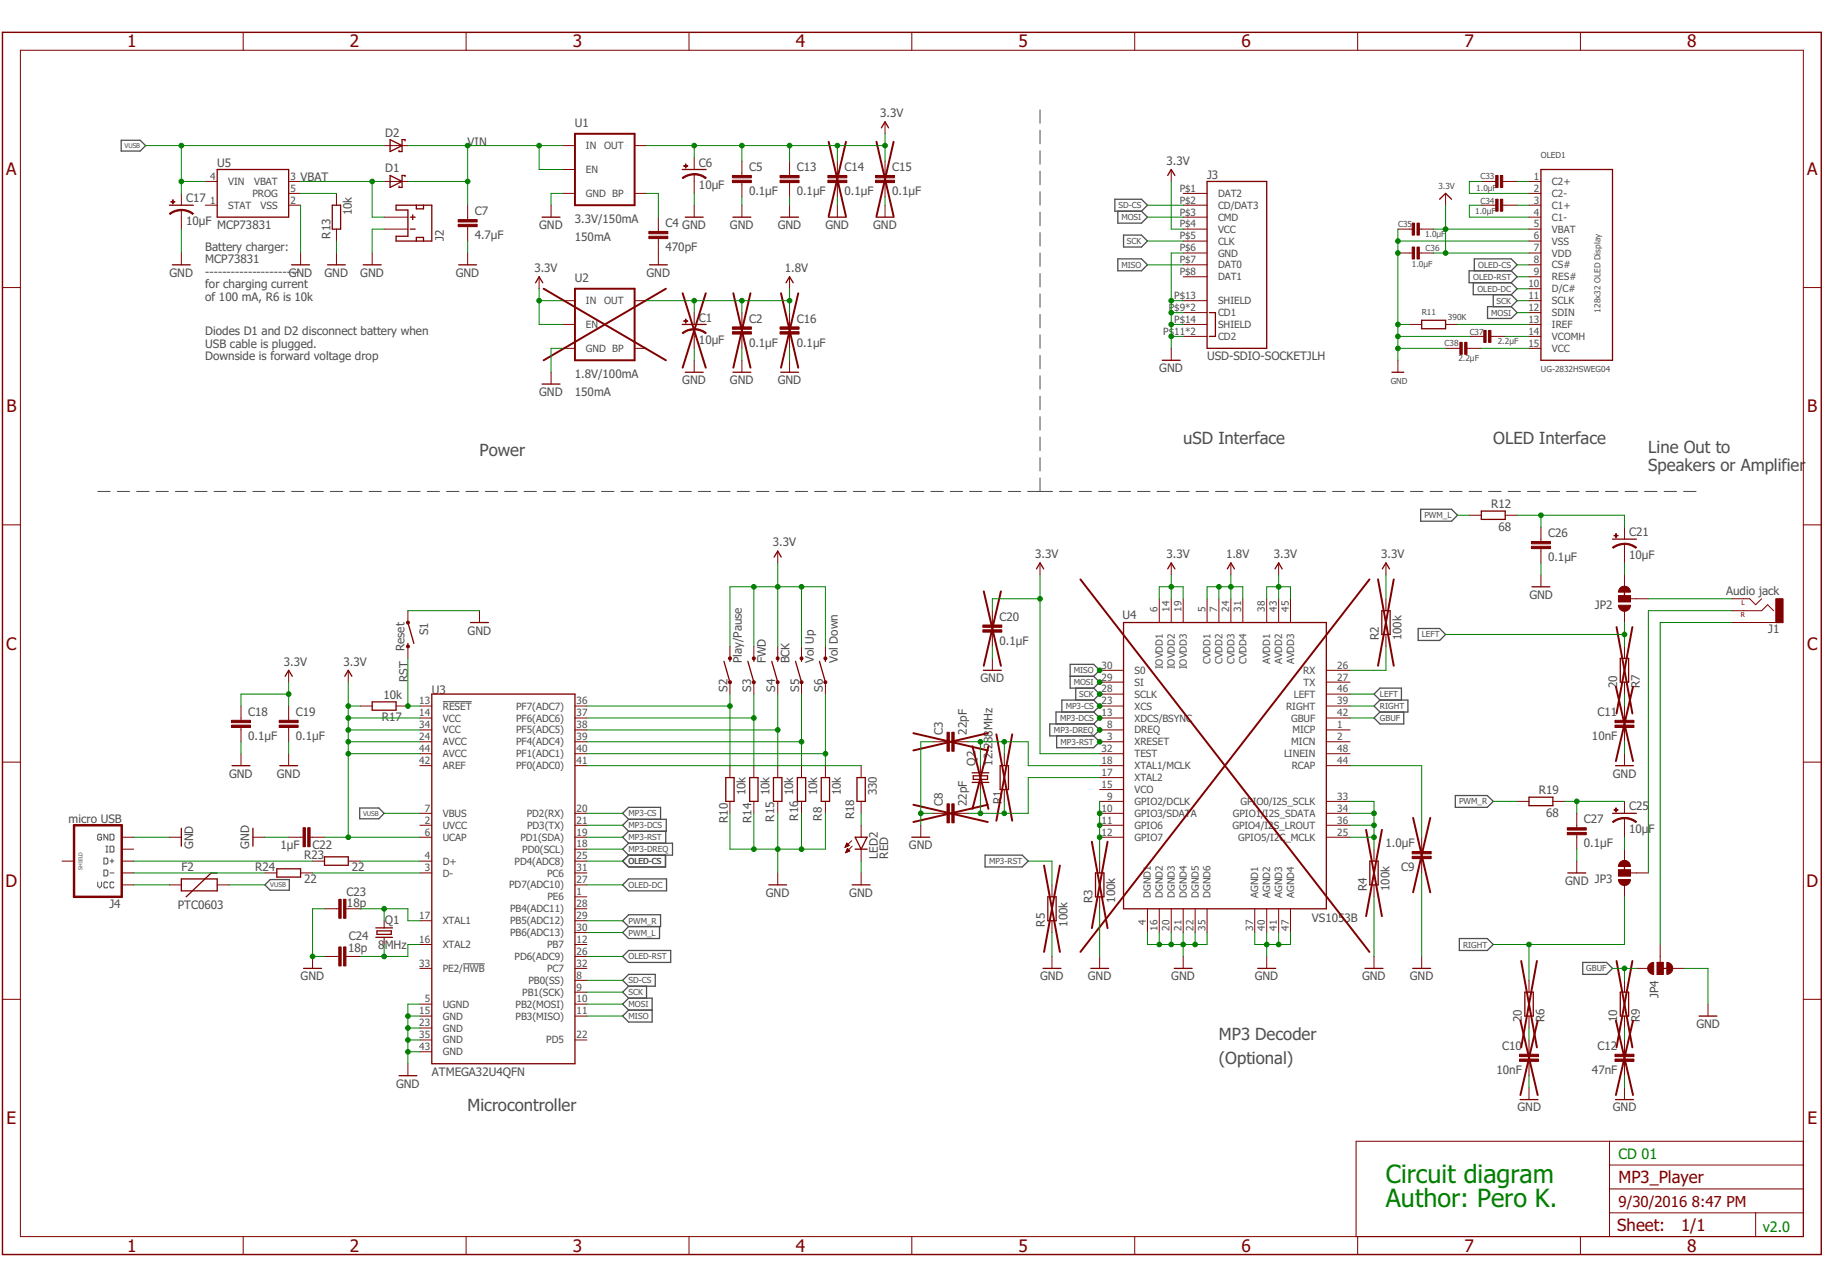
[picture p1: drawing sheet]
<svg xmlns="http://www.w3.org/2000/svg" width="297mm" height="210mm" viewBox="0 0 297 210" stroke-linecap="round" stroke-linejoin="round" font-family="sans-serif">
<defs><g id="words">
<g font-size="4.1" fill="#008000">
<text x="225.8" y="192.8">Circuit diagram</text>
<text x="225.8" y="196.7">Author: Pero K.</text>
</g>
<g font-size="2.8" fill="#800000">
<text x="20.7" y="7.7">1</text>
<text x="57" y="7.7">2</text>
<text x="93.3" y="7.7">3</text>
<text x="129.7" y="7.7">4</text>
<text x="166" y="7.7">5</text>
<text x="202.3" y="7.7">6</text>
<text x="238.6" y="7.7">7</text>
<text x="274.9" y="7.7">8</text>
<text x="1" y="28.5">A</text>
<text x="294.4" y="28.5">A</text>
<text x="1" y="67.2">B</text>
<text x="294.5" y="67.2">B</text>
<text x="1" y="105.9">C</text>
<text x="294.4" y="105.9">C</text>
<text x=".9" y="144.5">D</text>
<text x="294.3" y="144.5">D</text>
<text x="1.1" y="183.2">E</text>
<text x="294.5" y="183.2">E</text>
<text x="20.7" y="204">1</text>
<text x="57" y="204">2</text>
<text x="93.3" y="204">3</text>
<text x="129.7" y="204">4</text>
<text x="166" y="204">5</text>
<text x="202.3" y="204">6</text>
<text x="238.6" y="204">7</text>
<text x="274.9" y="204">8</text>
</g>
<g font-size="2.7" fill="#505050">
<text x="78.1" y="74.3">Power</text>
<text x="192.8" y="72.3">uSD Interface</text>
<text x="243.3" y="72.3">OLED Interface</text>
<text x="268.6" y="73.8">Line Out to</text>
<text x="268.6" y="76.7">Speakers or Amplifier</text>
<text x="198.6" y="169.5">MP3 Decoder</text>
<text x="198.6" y="173.4">(Optional)</text>
<text x="76.2" y="181.1">Microcontroller</text>
</g>
<g font-size="2.7" fill="#800000">
<text x="263.7" y="192.8">MP3_Player</text>
<text x="263.5" y="200.7">Sheet:</text>
<text x="273.9" y="200.6">1/1</text>
</g>
<g font-size="2.5" fill="#800000">
<text x="263.7" y="196.7">9/30/2016</text>
<text x="275.7" y="196.7">8:47 PM</text>
</g>
<g font-size="2.3" fill="#008000">
<text x="263.7" y="188.9">CD 01</text>
<text x="287.2" y="200.8">v2.0</text>
</g>
<g font-size="1.9" fill="#505050">
<text x="62.8" y="22.3">D2</text>
<text x="76.2" y="23.7">VIN</text>
<text x="93.7" y="20.6">U1</text>
<text x="143.4" y="19.1">3.3V</text>
<text x="35.4" y="27.2">U5</text>
<text x="49" y="29.6">VBAT</text>
<text x="62.8" y="28.1">D1</text>
<text x="113.9" y="27.1">C6</text>
<text x="122.1" y="27.9">C5</text>
<text x="129.8" y="27.9">C13</text>
<text x="137.6" y="27.9">C14</text>
<text x="145.4" y="27.9">C15</text>
<text x="190.1" y="26.8">3.3V</text>
<text x="196.7" y="29.2">J3</text>
<text x="30.3" y="33">C17</text>
<text x="57.3" y="35.1" transform="rotate(-90 57.3 35.1)">10k</text>
<text x="77.4" y="35.1">C7</text>
<text x="113.9" y="30.8">10µF</text>
<text x="122.1" y="31.8">0.1µF</text>
<text x="129.8" y="31.8">0.1µF</text>
<text x="137.6" y="31.8">0.1µF</text>
<text x="145.4" y="31.8">0.1µF</text>
<text x="30.3" y="36.7">10µF</text>
<text x="33.4" y="40.9">Battery charger:</text>
<text x="35.4" y="37.3">MCP73831</text>
<text x="53.9" y="38.9" transform="rotate(-90 53.9 38.9)">R13</text>
<text x="72.3" y="39.3" transform="rotate(-90 72.3 39.3)">J2</text>
<text x="77.4" y="39">4.7μF</text>
<text x="87.8" y="37.3">GND</text>
<text x="93.7" y="39.3">150mA</text>
<text x="93.7" y="36.4">3.3V/150mA</text>
<text x="108.4" y="40.9">470pF</text>
<text x="108.4" y="37">C4 GND</text>
<text x="118.9" y="37.3">GND</text>
<text x="126.7" y="37.3">GND</text>
<text x="134.5" y="37.3">GND</text>
<text x="142.3" y="37.3">GND</text>
<text x="27.6" y="45.1">GND</text>
<text x="33.4" y="42.9">MCP73831</text>
<text x="33.4" y="44.9">--------------------GND</text>
<text x="33.4" y="47">for charging current</text>
<text x="47.4" y="44.9">--</text>
<text x="52.9" y="45.1">GND</text>
<text x="58.7" y="45.1">GND</text>
<text x="74.2" y="45.1">GND</text>
<text x="87.1" y="44.3">3.3V</text>
<text x="93.7" y="45.9">U2</text>
<text x="105.3" y="45.1">GND</text>
<text x="127.9" y="44.3">1.8V</text>
<text x="33.4" y="49">of 100 mA, R6 is 10k</text>
<text x="113.9" y="52.4">C1</text>
<text x="122.1" y="52.6">C2</text>
<text x="129.8" y="52.6">C16</text>
<text x="33.4" y="54.6">Diodes D1 and D2 disconnect battery when</text>
<text x="33.4" y="56.7">USB cable is plugged.</text>
<text x="33.4" y="58.7">Downside is forward voltage drop</text>
<text x="113.9" y="56.1">10µF</text>
<text x="122.1" y="56.5">0.1µF</text>
<text x="129.8" y="56.5">0.1µF</text>
<text x="196.7" y="58.7">USD-SDIO-SOCKETJLH</text>
<text x="87.8" y="64.5">GND</text>
<text x="93.7" y="64.5">150mA</text>
<text x="93.7" y="61.6">1.8V/100mA</text>
<text x="111.2" y="62.6">GND</text>
<text x="118.9" y="62.6">GND</text>
<text x="126.7" y="62.6">GND</text>
<text x="188.9" y="60.7">GND</text>
<text x="243" y="82.8">R12</text>
<text x="125.9" y="89">3.3V</text>
<text x="244.2" y="86.5">68</text>
<text x="252.3" y="87.6">C26</text>
<text x="265.5" y="87.4">C21</text>
<text x="168.7" y="91">3.3V</text>
<text x="190.1" y="91">3.3V</text>
<text x="199.8" y="91">1.8V</text>
<text x="207.6" y="91">3.3V</text>
<text x="225" y="91">3.3V</text>
<text x="252.3" y="91.5">0.1µF</text>
<text x="265.5" y="91.1">10µF</text>
<text x="162.9" y="101.2">C20</text>
<text x="182.9" y="100.9">U4</text>
<text x="249.2" y="97.6">GND</text>
<text x="259.9" y="99.2">JP2</text>
<text x="281.3" y="97">Audio jack</text>
<text x="65.9" y="106.1" transform="rotate(-90 65.9 106.1)">Reset</text>
<text x="69.8" y="103.6" transform="rotate(-90 69.8 103.6)">S1</text>
<text x="76.2" y="103.4">GND</text>
<text x="162.9" y="105.1">0.1µF</text>
<text x="224.7" y="104.4" transform="rotate(-90 224.7 104.4)">R2</text>
<text x="228.3" y="104.4" transform="rotate(-90 228.3 104.4)">100k</text>
<text x="288.1" y="103.2">J1</text>
<text x="46.3" y="108.5">3.3V</text>
<text x="56" y="108.5">3.3V</text>
<text x="62.5" y="113.9">10k</text>
<text x="66.5" y="111.2" transform="rotate(-90 66.5 111.2)">RST</text>
<text x="70.4" y="113.1">U3</text>
<text x="118.5" y="112.7" transform="rotate(-90 118.5 112.7)">S2</text>
<text x="120.9" y="108.1" transform="rotate(-90 120.9 108.1)">Play/Pause</text>
<text x="122.4" y="112.7" transform="rotate(-90 122.4 112.7)">S3</text>
<text x="124.8" y="108.1" transform="rotate(-90 124.8 108.1)">FWD</text>
<text x="126.3" y="112.7" transform="rotate(-90 126.3 112.7)">S4</text>
<text x="128.7" y="108.1" transform="rotate(-90 128.7 108.1)">BCK</text>
<text x="130.2" y="112.7" transform="rotate(-90 130.2 112.7)">S5</text>
<text x="132.6" y="108.1" transform="rotate(-90 132.6 108.1)">Vol Up</text>
<text x="134.1" y="112.7" transform="rotate(-90 134.1 112.7)">S6</text>
<text x="136.5" y="108.1" transform="rotate(-90 136.5 108.1)">Vol Down</text>
<text x="159.8" y="111.2">GND</text>
<text x="263.5" y="112.1" transform="rotate(-90 263.5 112.1)">20</text>
<text x="267.2" y="112.1" transform="rotate(-90 267.2 112.1)">R7</text>
<text x="40.4" y="116.7">C18</text>
<text x="48.2" y="116.7">C19</text>
<text x="62.2" y="117.6">R17</text>
<text x="153.6" y="119.7" transform="rotate(-90 153.6 119.7)">C3</text>
<text x="157.5" y="119.7" transform="rotate(-90 157.5 119.7)">22pF</text>
<text x="260.3" y="116.7">C11</text>
<text x="40.4" y="120.6">0.1µF</text>
<text x="48.2" y="120.6">0.1µF</text>
<text x="159" y="124.8" transform="rotate(-90 159 124.8)">Q2</text>
<text x="161.7" y="124.8" transform="rotate(-90 161.7 124.8)">12.288MHz</text>
<text x="259.4" y="120.6">10nF</text>
<text x="37.3" y="126.7">GND</text>
<text x="45.1" y="126.7">GND</text>
<text x="121.5" y="129.6" transform="rotate(-90 121.5 129.6)">10k</text>
<text x="125.4" y="129.6" transform="rotate(-90 125.4 129.6)">10k</text>
<text x="129.2" y="129.6" transform="rotate(-90 129.2 129.6)">10k</text>
<text x="133.1" y="129.6" transform="rotate(-90 133.1 129.6)">10k</text>
<text x="137" y="129.6" transform="rotate(-90 137 129.6)">10k</text>
<text x="142.8" y="129.6" transform="rotate(-90 142.8 129.6)">330</text>
<text x="153.6" y="131.4" transform="rotate(-90 153.6 131.4)">C8</text>
<text x="157.5" y="131.4" transform="rotate(-90 157.5 131.4)">22pF</text>
<text x="163.2" y="131.1" transform="rotate(-90 163.2 131.1)">R1</text>
<text x="250.7" y="129.5">R19</text>
<text x="262.8" y="126.7">GND</text>
<text x="11.2" y="134.1">micro USB</text>
<text x="118.6" y="134.1" transform="rotate(-90 118.6 134.1)">R10</text>
<text x="122.5" y="134.1" transform="rotate(-90 122.5 134.1)">R14</text>
<text x="126.2" y="133.9" transform="rotate(-90 126.2 133.9)">R15</text>
<text x="130" y="133.7" transform="rotate(-90 130 133.7)">R16</text>
<text x="133.9" y="133.7" transform="rotate(-90 133.9 133.7)">R8</text>
<text x="139.2" y="133.5" transform="rotate(-90 139.2 133.5)">R18</text>
<text x="251.9" y="133.1">68</text>
<text x="258.1" y="134.2">C27</text>
<text x="265.5" y="135.8">10µ</text>
<text x="265.5" y="132.1">C25</text>
<text x="268.6" y="135.8">F</text>
<text x="29.6" y="141.9">F2</text>
<text x="31.5" y="138.4" transform="rotate(-90 31.5 138.4)">GND</text>
<text x="40.6" y="138.3" transform="rotate(-90 40.6 138.3)">GND</text>
<text x="41.6" y="141.9">R24</text>
<text x="45.7" y="138.3">1µF</text>
<text x="49.6" y="143.8">22</text>
<text x="49.6" y="140">R23</text>
<text x="50.9" y="138.3">C22</text>
<text x="57.3" y="141.9">22</text>
<text x="143" y="139.9" transform="rotate(-90 143 139.9)">LED2</text>
<text x="144.7" y="139.9" transform="rotate(-90 144.7 139.9)">RED</text>
<text x="148.1" y="138.4">GND</text>
<text x="225.8" y="138.1">1.0µF</text>
<text x="228.3" y="142">C9</text>
<text x="258.1" y="138.1">0.1µF</text>
<text x="17.8" y="147.9">J4</text>
<text x="29" y="148.1">PTC0603</text>
<text x="56.5" y="146.1">C23</text>
<text x="56.5" y="147.8">18p</text>
<text x="124.8" y="146.2">GND</text>
<text x="138.4" y="146.2">GND</text>
<text x="178" y="147.1" transform="rotate(-90 178 147.1)">R3</text>
<text x="181.7" y="147.1" transform="rotate(-90 181.7 147.1)">100k</text>
<text x="222.7" y="145.2" transform="rotate(-90 222.7 145.2)">R4</text>
<text x="226.4" y="145.2" transform="rotate(-90 226.4 145.2)">100k</text>
<text x="255" y="144.2">GND JP3</text>
<text x="56.7" y="155.2">18p</text>
<text x="56.8" y="153.2">C24</text>
<text x="61.6" y="154.7">8MHz</text>
<text x="62.7" y="150.6">Q1</text>
<text x="170.3" y="151" transform="rotate(-90 170.3 151)">R5</text>
<text x="173.9" y="151" transform="rotate(-90 173.9 151)">100k</text>
<text x="213.8" y="150.2">VS1053B</text>
<text x="49" y="159.8">GND</text>
<text x="169.5" y="159.8">GND</text>
<text x="177.2" y="159.8">GND</text>
<text x="190.8" y="159.8">GND</text>
<text x="204.4" y="159.8">GND</text>
<text x="221.9" y="159.8">GND</text>
<text x="229.7" y="159.8">GND</text>
<text x="248" y="166.6" transform="rotate(-90 248 166.6)">20</text>
<text x="251.6" y="166.6" transform="rotate(-90 251.6 166.6)">R6</text>
<text x="263.5" y="166.6" transform="rotate(-90 263.5 166.6)">10</text>
<text x="267.2" y="166.6" transform="rotate(-90 267.2 166.6)">R9</text>
<text x="270.2" y="162.6" transform="rotate(-90 270.2 162.6)">JP4</text>
<text x="276.4" y="167.5">GND</text>
<text x="244.8" y="171.1">C10</text>
<text x="260.3" y="171.1">C12</text>
<text x="64.5" y="177.2">GND</text>
<text x="70.4" y="175.3">ATMEGA32U4QFN</text>
<text x="243.8" y="175">10nF</text>
<text x="259.4" y="175">47nF</text>
<text x="247.3" y="181.1">GND</text>
<text x="262.8" y="181.1">GND</text>
</g>
<g font-size="1.6" fill="#505050">
<text x="34.2" y="29.3">4</text>
<text x="47.3" y="29.3">3</text>
<text x="95.5" y="24.3">IN</text>
<text x="95.5" y="28.2">EN</text>
<text x="98.5" y="24.3">OUT</text>
<text x="249.9" y="29.3">1</text>
<text x="34.2" y="33.2">1</text>
<text x="37.2" y="30.1">VIN</text>
<text x="37.2" y="34">STAT</text>
<text x="41.1" y="32.1">PROG</text>
<text x="41.4" y="30.1">VBAT</text>
<text x="42.5" y="34">VSS</text>
<text x="47.3" y="31.2">5</text>
<text x="47.3" y="33.2">2</text>
<text x="95.5" y="32.1">GND BP</text>
<text x="192.2" y="33.2">P$2</text>
<text x="192.2" y="35.1">P$3</text>
<text x="192.2" y="31.2">P$1</text>
<text x="198.5" y="34">CD/DAT3</text>
<text x="198.5" y="36">CMD</text>
<text x="198.5" y="32.1">DAT2</text>
<text x="249.9" y="31.2">2</text>
<text x="249.9" y="33.2">3</text>
<text x="249.9" y="35.1">4</text>
<text x="252.9" y="30.1">C2+</text>
<text x="252.9" y="32.1">C2-</text>
<text x="252.9" y="34">C1+</text>
<text x="252.9" y="36">C1-</text>
<text x="192.2" y="41">P$6</text>
<text x="192.2" y="37.1">P$4</text>
<text x="192.2" y="39">P$5</text>
<text x="198.5" y="41.8">GND</text>
<text x="198.5" y="37.9">VCC</text>
<text x="198.5" y="39.9">CLK</text>
<text x="249.9" y="37.1">5</text>
<text x="249.9" y="39">6</text>
<text x="249.9" y="41">7</text>
<text x="252.9" y="37.9">VBAT</text>
<text x="252.9" y="39.9">VSS</text>
<text x="252.9" y="41.8">VDD</text>
<text x="192.2" y="44.8">P$8</text>
<text x="192.2" y="42.9">P$7</text>
<text x="198.5" y="45.7">DAT1</text>
<text x="198.5" y="43.7">DAT0</text>
<text x="249" y="46.8">10</text>
<text x="249.9" y="42.9">8</text>
<text x="249.9" y="44.8">9</text>
<text x="252.9" y="43.7">CS#</text>
<text x="252.9" y="45.7">RES#</text>
<text x="252.9" y="47.6">D/C#</text>
<text x="95.5" y="49.6">IN</text>
<text x="95.5" y="53.5">EN</text>
<text x="98.5" y="49.6">OUT</text>
<text x="190.4" y="50.7">P$9*2</text>
<text x="191.3" y="52.6">P$14</text>
<text x="191.3" y="48.7">P$13</text>
<text x="198.5" y="53.5">SHIELD</text>
<text x="198.5" y="49.6">SHIELD</text>
<text x="198.5" y="51.5">CD1</text>
<text x="249" y="48.7">11</text>
<text x="249" y="50.7">12</text>
<text x="249" y="52.6">13</text>
<text x="252.9" y="49.6">SCLK</text>
<text x="252.9" y="51.5">SDIN</text>
<text x="252.9" y="53.5">IREF</text>
<text x="95.5" y="57.4">GND BP</text>
<text x="189.6" y="54.6">P$11*2</text>
<text x="198.5" y="55.4">CD2</text>
<text x="249" y="54.6">14</text>
<text x="249" y="56.5">15</text>
<text x="252.9" y="55.4">VCOMH</text>
<text x="252.9" y="57.4">VCC</text>
<text x="188.6" y="99.7" transform="rotate(-90 188.6 99.7)">6</text>
<text x="190.6" y="99.7" transform="rotate(-90 190.6 99.7)">14</text>
<text x="192.5" y="99.7" transform="rotate(-90 192.5 99.7)">19</text>
<text x="196.4" y="99.7" transform="rotate(-90 196.4 99.7)">5</text>
<text x="198.3" y="99.7" transform="rotate(-90 198.3 99.7)">7</text>
<text x="200.3" y="99.7" transform="rotate(-90 200.3 99.7)">24</text>
<text x="202.2" y="99.7" transform="rotate(-90 202.2 99.7)">31</text>
<text x="206.1" y="99.7" transform="rotate(-90 206.1 99.7)">38</text>
<text x="208.1" y="99.7" transform="rotate(-90 208.1 99.7)">43</text>
<text x="210" y="99.7" transform="rotate(-90 210 99.7)">45</text>
<text x="179.5" y="109">30</text>
<text x="179.5" y="110.9">29</text>
<text x="179.5" y="112.8">28</text>
<text x="184.9" y="109.8">S0</text>
<text x="184.9" y="111.8">SI</text>
<text x="184.9" y="113.7">SCLK</text>
<text x="189.5" y="109.1" transform="rotate(-90 189.5 109.1)">IOVDD1</text>
<text x="191.4" y="109.1" transform="rotate(-90 191.4 109.1)">IOVDD2</text>
<text x="193.4" y="109.1" transform="rotate(-90 193.4 109.1)">IOVDD3</text>
<text x="197.3" y="108.3" transform="rotate(-90 197.3 108.3)">CVDD1</text>
<text x="199.2" y="108.3" transform="rotate(-90 199.2 108.3)">CVDD2</text>
<text x="201.1" y="108.3" transform="rotate(-90 201.1 108.3)">CVDD3</text>
<text x="203.1" y="108.3" transform="rotate(-90 203.1 108.3)">CVDD4</text>
<text x="207" y="108.3" transform="rotate(-90 207 108.3)">AVDD1</text>
<text x="208.9" y="108.3" transform="rotate(-90 208.9 108.3)">AVDD2</text>
<text x="210.8" y="113.7">LEFT</text>
<text x="210.9" y="108.3" transform="rotate(-90 210.9 108.3)">AVDD3</text>
<text x="212.3" y="109.8">RX</text>
<text x="212.4" y="111.8">TX</text>
<text x="217.9" y="109">26</text>
<text x="217.9" y="110.9">27</text>
<text x="217.9" y="112.8">46</text>
<text x="68.3" y="114.8">13</text>
<text x="68.3" y="116.7">14</text>
<text x="68.3" y="118.7">34</text>
<text x="72.1" y="115.6">RESET</text>
<text x="72.1" y="117.6">VCC</text>
<text x="72.1" y="119.5">VCC</text>
<text x="84.1" y="119.5">PF5(ADC5)</text>
<text x="84.1" y="117.6">PF6(ADC6)</text>
<text x="84.1" y="115.6">PF7(ADC7)</text>
<text x="94" y="118.7">38</text>
<text x="94" y="116.7">37</text>
<text x="94" y="114.8">36</text>
<text x="179.5" y="114.8">23</text>
<text x="179.5" y="116.7">13</text>
<text x="180.4" y="118.7">8</text>
<text x="184.9" y="115.6">XCS</text>
<text x="184.9" y="117.6">XDCS/BSYNC</text>
<text x="184.9" y="119.5">DREQ</text>
<text x="209.6" y="115.6">RIGHT</text>
<text x="210.4" y="117.6">GBUF</text>
<text x="210.6" y="119.5">MICP</text>
<text x="217.9" y="114.8">39</text>
<text x="217.9" y="116.7">42</text>
<text x="217.9" y="118.7">1</text>
<text x="68.3" y="124.5">42</text>
<text x="68.3" y="120.6">24</text>
<text x="68.3" y="122.6">44</text>
<text x="72.1" y="125.4">AREF</text>
<text x="72.1" y="121.5">AVCC</text>
<text x="72.1" y="123.4">AVCC</text>
<text x="84.1" y="125.4">PF0(ADC0)</text>
<text x="84.1" y="123.4">PF1(ADC1)</text>
<text x="84.1" y="121.5">PF4(ADC4)</text>
<text x="94" y="124.5">41</text>
<text x="94" y="122.6">40</text>
<text x="94" y="120.6">39</text>
<text x="179.5" y="122.6">32</text>
<text x="179.5" y="124.5">18</text>
<text x="180.4" y="120.6">3</text>
<text x="184.9" y="121.5">XRESET</text>
<text x="184.9" y="123.4">TEST</text>
<text x="184.9" y="125.4">XTAL1/MCLK</text>
<text x="209.2" y="123.4">LINEIN</text>
<text x="210.4" y="121.5">MICN</text>
<text x="210.5" y="125.4">RCAP</text>
<text x="217.9" y="120.6">2</text>
<text x="217.9" y="122.6">48</text>
<text x="217.9" y="124.5">44</text>
<text x="179.5" y="126.5">17</text>
<text x="179.5" y="128.4">15</text>
<text x="180.4" y="130.3">9</text>
<text x="184.9" y="127.3">XTAL2</text>
<text x="184.9" y="129.2">VCO</text>
<text x="184.9" y="131.2">GPIO2/DCLK</text>
<text x="202.1" y="131.2">GPIO0/I2S_SCLK</text>
<text x="217.9" y="130.3">33</text>
<text x="69.2" y="136.2">6</text>
<text x="69.2" y="134.2">2</text>
<text x="69.2" y="132.3">7</text>
<text x="72.1" y="137">UCAP</text>
<text x="72.1" y="135.1">UVCC</text>
<text x="72.1" y="133.1">VBUS</text>
<text x="84.8" y="137">PD1(SDA)</text>
<text x="85.8" y="133.1">PD2(RX)</text>
<text x="85.9" y="135.1">PD3(TX)</text>
<text x="94" y="136.2">19</text>
<text x="94" y="132.3">20</text>
<text x="94" y="134.2">21</text>
<text x="179.5" y="132.3">10</text>
<text x="179.5" y="134.2">11</text>
<text x="179.5" y="136.2">12</text>
<text x="184.9" y="133.1">GPIO3/SDATA</text>
<text x="184.9" y="135.1">GPIO6</text>
<text x="184.9" y="137">GPIO7</text>
<text x="200.8" y="135.1">GPIO4/I2S_LROUT</text>
<text x="200.9" y="133.1">GPIO1/I2S_SDATA</text>
<text x="201.7" y="137">GPIO5/I2C_MCLK</text>
<text x="217.9" y="132.3">34</text>
<text x="217.9" y="134.2">36</text>
<text x="217.9" y="136.2">25</text>
<text x="69.2" y="140.1">4</text>
<text x="69.2" y="142">3</text>
<text x="72.1" y="140.9">D+</text>
<text x="72.1" y="142.9">D-</text>
<text x="83.8" y="140.9">PD4(ADC8)</text>
<text x="85.1" y="139">PD0(SCL)</text>
<text x="89.1" y="142.8">PC6</text>
<text x="94" y="142">31</text>
<text x="94" y="138.1">18</text>
<text x="94" y="140.1">25</text>
<text x="94" y="143.9">27</text>
<text x="68.3" y="149.8">17</text>
<text x="83" y="144.8">PD7(ADC10)</text>
<text x="83.1" y="148.7">PB4(ADC11)</text>
<text x="89.2" y="146.7">PE6</text>
<text x="94" y="147.8">28</text>
<text x="94" y="149.8">29</text>
<text x="94" y="145.9">1</text>
<text x="187.5" y="146.3" transform="rotate(-90 187.5 146.3)">DGND1</text>
<text x="189.5" y="146.3" transform="rotate(-90 189.5 146.3)">DGND2</text>
<text x="191.4" y="146.3" transform="rotate(-90 191.4 146.3)">DGND3</text>
<text x="193.4" y="146.3" transform="rotate(-90 193.4 146.3)">DGND4</text>
<text x="195.3" y="146.3" transform="rotate(-90 195.3 146.3)">DGND5</text>
<text x="197.3" y="146.3" transform="rotate(-90 197.3 146.3)">DGND6</text>
<text x="205" y="146.3" transform="rotate(-90 205 146.3)">AGND1</text>
<text x="207" y="146.3" transform="rotate(-90 207 146.3)">AGND2</text>
<text x="208.9" y="146.3" transform="rotate(-90 208.9 146.3)">AGND3</text>
<text x="210.9" y="146.3" transform="rotate(-90 210.9 146.3)">AGND4</text>
<text x="68.3" y="153.7">16</text>
<text x="72.1" y="150.6">XTAL1</text>
<text x="72.1" y="154.5">XTAL2</text>
<text x="83.1" y="150.6">PB5(ADC12)</text>
<text x="83.1" y="152.6">PB6(ADC13)</text>
<text x="89.2" y="154.5">PB7</text>
<text x="94" y="151.7">30</text>
<text x="94" y="153.7">12</text>
<text x="94" y="155.6">26</text>
<text x="186.7" y="150.8" transform="rotate(-90 186.7 150.8)">4</text>
<text x="188.6" y="151.7" transform="rotate(-90 188.6 151.7)">16</text>
<text x="190.6" y="151.7" transform="rotate(-90 190.6 151.7)">20</text>
<text x="192.5" y="151.7" transform="rotate(-90 192.5 151.7)">21</text>
<text x="194.5" y="151.7" transform="rotate(-90 194.5 151.7)">22</text>
<text x="196.4" y="151.7" transform="rotate(-90 196.4 151.7)">35</text>
<text x="204.2" y="151.7" transform="rotate(-90 204.2 151.7)">37</text>
<text x="206.1" y="151.7" transform="rotate(-90 206.1 151.7)">40</text>
<text x="208.1" y="151.7" transform="rotate(-90 208.1 151.7)">41</text>
<text x="210" y="151.7" transform="rotate(-90 210 151.7)">47</text>
<text x="68.3" y="157.5">33</text>
<text x="72.1" y="158.4">PE2/HWB</text>
<text x="83.8" y="156.5">PD6(ADC9)</text>
<text x="86.1" y="160.3">PB0(SS)</text>
<text x="89.1" y="158.4">PC7</text>
<text x="94" y="159.5">8</text>
<text x="94" y="161.4">9</text>
<text x="94" y="157.5">32</text>
<text x="68.3" y="165.3">15</text>
<text x="68.3" y="167.3">23</text>
<text x="69.2" y="163.4">5</text>
<text x="72.1" y="166.2">GND</text>
<text x="72.1" y="164.2">UGND</text>
<text x="84" y="164.2">PB2(MOSI)</text>
<text x="84" y="166.2">PB3(MISO)</text>
<text x="85.1" y="162.3">PB1(SCK)</text>
<text x="94" y="163.4">10</text>
<text x="94" y="165.3">11</text>
<text x="68.3" y="169.2">35</text>
<text x="68.3" y="171.1">43</text>
<text x="72.1" y="168.1">GND</text>
<text x="72.1" y="170.1">GND</text>
<text x="72.1" y="172">GND</text>
<text x="89" y="170.1">PD5</text>
<text x="94" y="169.2">22</text>
</g>
<g font-size="1.4" fill="#505050">
<text x="241.2" y="29.2">C33</text>
<text x="251.1" y="25.7">OLED1</text>
<text x="182.3" y="33.9">SD-CS</text>
<text x="182.7" y="35.9">MOSI</text>
<text x="234.4" y="30.7">3.3V</text>
<text x="240.4" y="34.8">1.0µF</text>
<text x="240.6" y="31.1">1.0µF</text>
<text x="241.2" y="33.3">C34</text>
<text x="183.6" y="39.8">SCK</text>
<text x="227.8" y="37">C35</text>
<text x="232.2" y="38.7">1.0µF</text>
<text x="232.3" y="40.8">C36</text>
<text x="182.7" y="43.7">MISO</text>
<text x="230.1" y="43.6">1.0µF</text>
<text x="240" y="45.6">OLED-RST</text>
<text x="240.7" y="47.5">OLED-DC</text>
<text x="240.9" y="43.7">OLED-CS</text>
<text x="231.7" y="51.3">R11</text>
<text x="235.9" y="52.2">390K</text>
<text x="243" y="51.4">MOSI</text>
<text x="243.9" y="49.5">SCK</text>
<text x="260.8" y="50.9" transform="rotate(-90 260.8 50.9)">128x32 OLED Display</text>
<text x="235.4" y="56.4">C38</text>
<text x="237.6" y="58.9">2.2µF</text>
<text x="239.5" y="54.6">C37</text>
<text x="244" y="56">2.2µF</text>
<text x="226.6" y="62.6">GND</text>
<text x="251.1" y="60.7">UG-2832HSWEG04</text>
<text x="232.1" y="84.5">PWM_L</text>
<text x="231.6" y="103.9">LEFT</text>
<text x="175" y="111.7">MOSI</text>
<text x="175" y="109.7">MISO</text>
<text x="175.8" y="113.6">SCK</text>
<text x="224.9" y="113.6">LEFT</text>
<text x="171.7" y="119.4">MP3-DREQ</text>
<text x="172.7" y="117.5">MP3-DCS</text>
<text x="173.6" y="115.6">MP3-CS</text>
<text x="224.9" y="115.5">RIGHT</text>
<text x="224.9" y="117.5">GBUF</text>
<text x="172.8" y="121.4">MP3-RST</text>
<text x="237.7" y="131.1">PWM_R</text>
<text x="102.4" y="133">MP3-CS</text>
<text x="102.4" y="135">MP3-DCS</text>
<text x="102.4" y="136.9">MP3-RST</text>
<text x="102.4" y="138.9">MP3-DREQ</text>
<text x="102.4" y="140.8">OLED-CS</text>
<text x="161.2" y="140.8">MP3-RST</text>
<text x="102.4" y="144.7">OLED-DC</text>
<text x="102.4" y="150.5">PWM_R</text>
<text x="102.4" y="152.5">PWM_L</text>
<text x="238.4" y="154.4">RIGHT</text>
<text x="102.4" y="156.4">OLED-RST</text>
<text x="102.4" y="160.2">SD-CS</text>
<text x="258.5" y="158.3">GBUF</text>
<text x="102.4" y="164.1">MOSI</text>
<text x="102.4" y="162.2">SCK</text>
<text x="102.4" y="166.1">MISO</text>
</g>
<g font-size="1.1" fill="#505050">
<text x="20.3" y="24.1">VUSB</text>
<text x="59.2" y="132.9">VUSB</text>
<text x="44" y="144.6">VUSB</text>
</g>
<g font-size="1.1" fill="#800000">
<text x="283.6" y="100.5">R</text>
<text x="283.8" y="98.6">L</text>
</g>
<text font-size=".9" fill="#505050" x="13.5" y="141.8" transform="rotate(-90 13.5 141.8)">SHIELD</text>
</g></defs>
<g fill="none" stroke="#505050" stroke-width=".17">
<path d="M169.5 17.9v2.2M169.5 21.2v2.2M169.5 24.6v2.2M169.5 27.9v2.2M169.5 31.2v2.2M169.5 34.6v2.2M169.5 37.9v2.2M169.5 41.2v2.2M169.5 44.6v2.2M169.5 47.9v2.2M169.5 51.2v2.2M169.5 54.6v2.1"/>
<path d="M169.5 57.9v2.2M169.5 61.2v2.2M169.5 64.6v2.2M169.5 67.9v2.2M169.5 71.2v2.2M169.5 74.6v2.2M169.5 77.9v2.2M15.9 80.1h2M19.1 80.1h2M22.3 80.1h2M25.4 80.1h2M28.6 80.1h2"/>
<path d="M31.7 80.1h2M34.9 80.1h2M38 80.1h2M41.2 80.1h2M44.4 80.1h2M47.5 80.1h2M50.7 80.1h2M53.8 80.1h2M57 80.1h2M60.1 80.1h2M63.3 80.1h2M66.4 80.1h2.1"/>
<path d="M69.6 80.1h2M72.8 80.1h2M75.9 80.1h2M79.1 80.1h2M82.2 80.1h2M85.4 80.1h2M88.5 80.1h2.1M91.7 80.1h2M94.9 80.1h2M98 80.1h2M101.2 80.1h2M104.3 80.1h2"/>
<path d="M107.5 80.1h2M110.6 80.1h2M113.8 80.1h2M116.9 80.1h2.1M120.1 80.1h2M123.3 80.1h2M126.4 80.1h2M129.6 80.1h2M132.7 80.1h2M135.9 80.1h2M139 80.1h2.1M142.2 80.1h2"/>
<path d="M145.4 80.1h2M148.5 80.1h2M151.7 80.1h2M154.8 80.1h2M158 80.1h2M161.1 80.1h2.1M164.3 80.1h2M167.4 80.1h4.1M172.6 80.1h2.1M175.8 80.1h2M179 80.1h2M182.2 80.1h2"/>
<path d="M185.4 80.1h2M188.5 80.1h2.1M191.7 80.1h2M194.9 80.1h2M198.1 80.1h2M201.2 80.1h2.1M204.4 80.1h2M207.6 80.1h2M210.8 80.1h2M214 80.1h2M217.1 80.1h2.1M220.3 80.1h2"/>
<path d="M223.5 80.1h2M226.7 80.1h2M229.8 80.1h2.1M233 80.1h2M236.2 80.1h2M239.4 80.1h2M242.5 80.1h2.1M245.7 80.1h2.1M248.9 80.1h2M252.1 80.1h2M255.2 80.1h2.1M258.4 80.1h2.1"/>
<path d="M261.6 80.1h2M264.8 80.1h2M268 80.1h2M271.1 80.1h2.1M274.3 80.1h2.1"/>
</g>
<g fill="none" stroke="#505050" stroke-width=".16">
<path d="M72.2 114.3h4.7M16.6 136.1l-.2-.1h-.3l-.2 .1v.7l.2 .1h.3l.2-.1v-.4h-.4M16.9 139.8h.5l.2 .2v.6l-.2 .2h-.5zM17.3 138.9h.3M17.3 137.9h.3M17.4 137.9v1M17.6 136v.9l-.7-.9v.9M17.9 136h.5l.2 .1v.7l-.2 .1h-.5zM17.9 137.9h.5l.2 .2v.6l-.2 .2h-.5zM18.2 140v.6M15.9 143.7v.7l.3 .3 .4-.3v-.7M16.9 141.8h.5l.2 .1v.7l-.2 .1h-.5z"/>
<path d="M17.6 143.9l-.2-.2h-.3l-.2 .2v.6l.2 .2h.3l.2-.2M17.9 142.3h.7M17.9 140.3h.7M18.6 143.9l-.2-.2h-.3l-.2 .2v.6l.2 .2h.3l.2-.2M75.5 157.1h3.5"/>
</g>
<g fill="none" stroke="#505050" stroke-width=".21">
<path d="M19.7 22.9h3.1l.9 .8-.9 .9h-3.1zM181.7 32.5h4.3l1 .9-1 1h-4.3zM182.1 34.4v2h3.9l1-1-1-1M183.1 38.3h2.9l1 1-1 1h-2.9zM182.1 42.2h3.9l1 1-1 .9h-3.9zM240.1 46.1v1.9h6.1M240.2 44.1v-1.9h6l1 1-1 .9M242.4 50h3.8l1 .9-1 1h-3.8zM243.3 48v2M246.2 48l1 1-1 1M246.2 44.1h-6.8v2h6.8M246.2 44.1l1 1-1 1"/>
<path d="M246.2 46.1l1 1-1 .9M231.5 83h5l1 1-1 .9h-5zM172.2 119.9v2h6l1-1-1-1M174.4 110.2h3.8M175.3 112.1v2M178.2 110.2l1-1-1-.9h-3.8v3.8h3.8M178.2 114.1h-5.2v1.9M178.2 116h-6.1v2M178.2 118h-7.2v1.9h7.2M178.2 110.2l1 1-1 .9M178.2 112.1l1 1-1 1M178.2 116l1 1-1 1"/>
<path d="M178.2 114.1l1 1-1 .9M178.2 118l1 1-1 .9M224.9 114.1l-1-1 1-1h3.4v2M224.9 114.1h4.5v1.9h-4.5M224.9 114.1l-1 1 1 .9M224.9 116l-1 1 1 1h3.8v-2M231.1 102.4h3.5l.9 1-.9 1h-3.5zM58.6 131.7h3.1l.9 .8-.9 .9h-3.1zM102.4 133.5l-.9-1 .9-.9h5.2v1.9M102.4 133.5h6.2v2h-6.2M102.4 133.5l-.9 1 .9 1M102.4 139.4l-.9 .9 .9 1h6v-1.9"/>
<path d="M102.4 137.4h7.2v2h-7.2M102.4 135.5l-.9 .9 .9 1M102.4 137.4l-.9 1 .9 1M108.5 135.5v1.9M160.5 139.4h6.1l.9 .9-.9 1h-6.1zM237.1 129.6h5.2l1 1-1 1h-5.2zM43.2 144.2l.8-.9h3.1v1.8h-3.1zM101.5 159.8l.9-1h4.4v1.9h-4.4zM101.5 150.1l.9-1h5.2v1.9h-5.2zM101.5 144.2l.9-1h6.2v2h-6.2zM102.4 151l-.9 1 .9 1h5.1v-2M102.4 154.9h6.9v1.9h-6.9l-.9-.9z"/>
<path d="M237.8 153h4.5l1 .9-1 1h-4.5zM257.9 156.8h3.9l.9 1-.9 1h-3.9zM102.4 162.7l-.9 .9 .9 1M102.4 162.7h3.9v3.9h-3.9l-.9-1 .9-1M102.4 164.6h3.9M102.4 160.7l-.9 1 .9 1M105.3 160.7v2"/>
</g>
<g fill="none" stroke="#800000" stroke-width=".32">
<path d="M93.7 21.8h9.7v11.6h-9.7zM135 23.1l2.8 12.1M137.8 23.1l-2.8 12.1M142.8 23.1l2.8 12.1M145.6 23.1l-2.8 12.1M88.6 47.1l19.9 11.6M93.7 47.1h9.7v11.6h-9.7zM108.5 47.1l-19.9 11.6M111.2 47.8l3.8 12.1M115 47.8l-3.8 12.1M119.5 47.8l2.8 12.1M122.3 47.8l-2.8 12.1"/>
<path d="M127.3 47.8l2.8 12.1M130.1 47.8l-2.8 12.1M160.3 96.4l2.8 12.1M163.1 96.4l-2.8 12.1M176 94.4l47.1 60.7M223.1 94.4l-47.1 60.7M224.5 94.4l2.6 14.1M227.1 94.4l-2.6 14.1M148.8 119.5l12.2 2.8M161 119.5l-12.2 2.8M162.3 119.7l2.6 14.1M164.9 119.7l-2.6 14.1"/>
<path d="M263.3 111.9l2.8 12.1M263.4 102.2l2.6 14.1M266 102.2l-2.6 14.1M266.1 111.9l-2.8 12.1M148.8 131.1l12.2 2.9M158.5 121.6l2.6 10.2M161 131.1l-12.2 2.9M161.1 121.6l-2.6 10.2M177.9 137.2l2.6 14.1M180.5 137.2l-2.6 14.1M222.6 135.2l2.6 14.1M225.2 135.2l-2.6 14.1"/>
<path d="M230.3 133.3l2.7 12.1M233 133.3l-2.7 12.1M170.1 141.1l2.6 14M172.7 141.1l-2.6 14M247.9 156.6l2.5 14.1M250.4 156.6l-2.5 14.1M263.4 156.6l2.6 14.1M266 156.6l-2.6 14.1M247.7 166.3l2.8 12.2M250.5 166.3l-2.8 12.2M263.3 166.3l2.8 12.2M266.1 166.3l-2.8 12.2"/>
</g>
<g fill="none" stroke="#800000" stroke-width=".16">
<path d="M3.3 8.2h290.5v193.3h-290.5zM39.6 5.3v2.9M75.9 5.3v2.9M112.3 5.3v2.9M144.2 19.9v1.9M148.6 5.3v2.9M184.9 5.3v2.9M221.2 5.3v2.9M257.5 5.3v2.9M29.5 31.5v1.9M29.5 34.2v3.1M33.4 29.6h2"/>
<path d="M33.4 33.4h2M47 31.5h2M47 29.6h2M47 33.4h2M54.8 31.5v1.9M54.8 37.3v2M62.6 23.7h3.9M62.6 29.6h3.9M62.6 37.3h3.9M62.6 35.4h3.9M76.2 33.4v2.4M76.2 37v2.3"/>
<path d="M89.8 33.4v2M91.7 23.7h2M91.7 31.5h2M91.7 27.6h2M103.4 23.7h1.9M103.4 31.5h1.9M107.3 35.4v2.3M107.3 38.9v4.3M113.1 25.7v1.9M113.1 28.4v3.1M113.1 33.4v2M120.9 26.3v2.3"/>
<path d="M120.9 29.8v2.3M120.9 33.4v2M128.7 26.3v2.3M128.7 29.8v2.3M128.7 33.4v2M136.4 26.3v2.3M136.4 29.8v2.3M136.4 33.4v2M144.2 26.3v2.3M144.2 29.8v2.3M144.2 33.4v2M190.8 27.6v2"/>
<path d="M192.8 31.5h3.9M192.8 33.4h3.9M192.8 37.3h3.9M192.8 35.4h3.9M192.8 39.3h3.9M227.8 37.3h2.5M231.1 37.3h2.5M235.5 31.5v1.9M241.4 29.6h2.5M241.4 33.4h2.5M244.7 29.6h2.5M244.7 33.4h2.5"/>
<path d="M249.1 31.5h2M249.1 29.6h2M249.1 33.4h2M249.1 37.3h2M249.1 35.4h2M249.1 39.3h2M.4 46.9h2.9M29.5 41.2v2M49 41.2v2M54.8 41.2v2M60.6 41.2v2M76.2 41.2v2"/>
<path d="M87.8 45.1v2M91.7 49h2M91.7 56.8h2M91.7 52.9h2M103.4 49h1.9M103.4 56.8h1.9M113.1 50.9v2M113.1 53.7v3.1M113.1 58.7v2M120.9 50.9v2.4M120.9 54.4v2.4M120.9 58.7v2"/>
<path d="M128.7 45.1v2M128.7 50.9v2.4M128.7 54.4v2.4M128.7 58.7v2M190.8 56.8v1.9M192.8 49h3.9M192.8 52.9h3.9M192.8 41.2h3.9M192.8 43.2h3.9M192.8 45.1h3.9M192.8 50.9h3.9M192.8 54.8h3.9"/>
<path d="M227.8 41.2h2.5M227.8 58.7v2M229.7 52.9h1.9M231.1 41.2h2.5M235.5 56.8h2.6M235.5 52.9h2M238.8 56.8h2.6M239.4 54.8h2.6M242.7 54.8h2.6M249.1 49h2M249.1 56.8h2M249.1 52.9h2"/>
<path d="M249.1 41.2h2M249.1 43.2h2M249.1 45.1h2M249.1 47.1h2M249.1 50.9h2M249.1 54.8h2M293.8 46.9h3M89.8 60.7v1.9M.4 85.5h2.9M66.5 99.5v2M78.1 99.5v2M126.7 89.8v1.9"/>
<path d="M161.7 99.5v2.4M169.5 91.7v2M188.9 97.6v3.9M190.8 91.7v2M190.8 97.6v3.9M192.8 97.6v3.9M196.7 97.6v3.9M198.6 97.6v3.9M200.6 91.7v2M200.6 97.6v3.9M202.5 97.6v3.9M206.4 97.6v3.9"/>
<path d="M208.3 91.7v2M208.3 97.6v3.9M210.3 97.6v3.9M225.8 91.7v2M225.8 97.6v1.9M239.4 84h2M245.3 84h1.9M251.1 85.9v2.3M251.1 89.4v2.3M251.1 93.7v1.9M263.7 97.1h2v1h-2zM264.7 85.9v2"/>
<path d="M264.7 88.6v3.1M264.7 93.7v1.9M264.7 99.5v2M265.7 97.6h2.9M282.2 97.6h2.9l1 1 .9-1M282.2 99.5h4.8l1-.9 1 .9M293.8 85.5h3M39.3 115.1v2.3M39.3 118.6v2.3M47 109.2v2M47 115.1v2.3M47 118.6v2.3"/>
<path d="M56.7 109.2v2M58.7 115.1h1.9M64.5 115.1h2M66.5 105.3v2M68.4 115.1h2M68.4 117h2M68.4 119h2M93.7 115.1h1.9M93.7 117h1.9M93.7 119h1.9M118.9 105.3v2M118.9 111.2v1.9"/>
<path d="M122.8 105.3v2M122.8 111.2v1.9M126.7 105.3v2M126.7 111.2v1.9M130.6 105.3v2M130.6 111.2v1.9M134.5 105.3v2M134.5 111.2v1.9M161.7 103v2.3M161.7 107.3v1.9M179.2 109.2h3.9M179.2 111.2h3.9"/>
<path d="M179.2 113.1h3.9M179.2 115.1h3.9M179.2 117h3.9M179.2 119h3.9M216.1 109.2h3.9M216.1 111.2h3.9M216.1 113.1h3.9M216.1 115.1h3.9M216.1 117h3.9M216.1 119h3.9M225.8 103.4v1.9M264.7 105.3v2"/>
<path d="M264.7 111.2v1.9M264.7 115.1v2.3M264.7 118.6v2.3M282.2 101.5h7.7M.4 124.2h2.9M19.8 136.4h2M19.8 138.4h2M27.6 136.4h1.9M39.3 122.8v2M41.2 136.4h2M47 136.4h2.4M47 122.8v2"/>
<path d="M50.5 136.4h2.4M68.4 120.9h2M68.4 122.8h2M68.4 124.8h2M68.4 132.5h2M68.4 134.5h2M68.4 136.4h2M93.7 120.9h1.9M93.7 122.8h1.9M93.7 124.8h1.9M93.7 132.5h1.9M93.7 134.5h1.9"/>
<path d="M93.7 136.4h1.9M93.7 138.4h1.9M118.9 124.8v1.9M118.9 130.6v1.9M122.8 124.8v1.9M122.8 130.6v1.9M126.7 124.8v1.9M126.7 130.6v1.9M130.6 124.8v1.9M130.6 130.6v1.9M134.5 124.8v1.9M134.5 130.6v1.9"/>
<path d="M137.7 138h.2M137.8 137.9h.3M137.8 137.8h.5M137.8 139h.1M137.8 138.9h.2M137.9 137.7h.4M137.9 138.8h.3M137.9 137.6h.3M137.9 138.7h.5M137.9 137.5h.2M137.9 138.6h.5M138 137.4l-.3 .7"/>
<path d="M138 137.4l.4 .4-.7 .3M138 137.4h.1M138 138.5h.3M138 138.4h.2M138 138.3h.2M138.1 138.3l.4 .4-.7 .3zM138.8 137l-1.1 1.1M138.9 137.9l-1.1 1.1M140.3 124.8v1.9M140.3 130.6v1.9M140.3 134.5v1.9M140.3 138.4v1.9"/>
<path d="M150 134.5v1.9M152 120.9h2.3M152 132.5h2.3M155.5 120.9h2.3M155.5 132.5h2.3M159.7 124.8v1.1M159.7 127.5v1.2M163.6 122.8v2M163.6 128.7v1.9M179.2 120.9h3.9M179.2 122.8h3.9M179.2 124.8h3.9"/>
<path d="M179.2 126.7h3.9M179.2 128.7h3.9M179.2 130.6h3.9M179.2 132.5h3.9M179.2 134.5h3.9M179.2 136.4h3.9M216.1 120.9h3.9M216.1 122.8h3.9M216.1 124.8h3.9M216.1 130.6h3.9M216.1 132.5h3.9M216.1 134.5h3.9"/>
<path d="M216.1 136.4h3.9M223.9 138.4v1.9M231.6 136.4v2.4M231.6 139.9v2.4M247.2 130.6h1.9M253 130.6h2M256.9 132.5v2.4M256.9 136.1v2.3M264.7 122.8v2M264.7 130.6v1.9M264.7 133.3v3.1M264.7 138.4v1.9"/>
<path d="M293.8 124.2h3M10.1 140.3h2M19.8 140.3h2M19.8 142.3h2M19.8 144.2h2M27.6 144.2h1.9M35.4 144.2h1.9M43.2 142.3h1.9M49 142.3h1.9M50.9 155.9v1.9M50.9 140.3h2M52.9 148.1h2.3"/>
<path d="M52.9 155.9h2.3M56.4 148.1h2.3M56.4 155.9h2.3M56.7 140.3h2M62.6 150.1v1.1M62.6 152.8v1.1M68.4 140.3h2M68.4 142.3h2M68.4 157.8h2M68.4 150.1h2M68.4 153.9h2M93.7 148.1h1.9"/>
<path d="M93.7 155.9h1.9M93.7 140.3h1.9M93.7 142.3h1.9M93.7 144.2h1.9M93.7 157.8h1.9M93.7 159.8h1.9M93.7 150.1h1.9M93.7 152h1.9M93.7 153.9h1.9M93.7 146.2h1.9M126.7 142.3v1.9M140.3 142.3v1.9"/>
<path d="M171.4 144.2v2M171.4 150.1v1.9M171.4 155.9v1.9M179.2 140.3v2M179.2 146.2v1.9M179.2 155.9v1.9M187 148.1v3.9M188.9 148.1v3.9M190.8 148.1v3.9M192.8 148.1v3.9M192.8 155.9v1.9M194.7 148.1v3.9"/>
<path d="M196.7 148.1v3.9M204.4 148.1v3.9M206.4 148.1v3.9M206.4 155.9v1.9M208.3 148.1v3.9M210.3 148.1v3.9M223.9 144.2v2M223.9 155.9v1.9M231.6 155.9v1.9M249.1 159.8v1.9M256.9 140.3v2M263.7 141.8h2v.9h-2z"/>
<path d="M264.7 144.2v2M264.7 159.8v1.9M265.7 142.3h2.9M266.6 157.8h2M270 156.8h1v2h-1zM270.5 153.9v2.9M272.5 157.8h1.9M.4 162.9h2.9M66.5 173.4v1.9M68.4 165.6h2M68.4 167.5h2M68.4 169.5h2"/>
<path d="M68.4 171.4h2M68.4 163.6h2M93.7 165.6h1.9M93.7 169.5h1.9M93.7 161.7h1.9M93.7 163.6h1.9M249.1 165.6v1.9M249.1 169.5v2.3M249.1 173v2.3M249.1 177.2v2M264.7 165.6v1.9M264.7 169.5v2.3"/>
<path d="M264.7 173v2.3M264.7 177.2v2M278.3 163.6v2M293.8 162.9h3M262.3 197.7h31.5M262.3 186v15.5M262.3 193.8h31.5M262.3 189.9h31.5M286.1 197.7v3.8M293.8 186h-72.8v15.5M39.6 201.5v2.9M75.9 201.5v2.9"/>
<path d="M112.3 201.5v2.9M148.6 201.5v2.9M184.9 201.5v2.9M221.2 201.5v2.9M257.5 201.5v2.9"/>
</g>
<g fill="#800000" stroke="#800000" stroke-width=".16">
<path d="M119.3 29.4h3.1v.4h-3.1z"/>
<path d="M119.3 28.6h3.1v.4h-3.1z"/>
<path d="M111.4 27h.7v.1h-.7z"/>
<path d="M111.7 26.7h.1v.7h-.1z"/>
<path d="M111.4 52.3h.7v.1h-.7z"/>
<path d="M111.7 52h.1v.7h-.1z"/>
<path d="M119.3 54.1h3.1v.3h-3.1z"/>
<path d="M119.3 53.3h3.1v.4h-3.1z"/>
<path d="M155.1 119.3h.4v3.1h-.4z"/>
<path d="M154.3 119.3h.4v3.1h-.4z"/>
<path d="M155.1 131h.4v3.1h-.4z"/>
<path d="M154.3 131h.4v3.1h-.4z"/>
<path d="M230.1 138.8h3.1v.3h-3.1z"/>
<path d="M230.1 139.6h3.1v.3h-3.1z"/>
<path d="M247.6 172.6h3.1v.4h-3.1z"/>
<path d="M247.6 171.8h3.1v.4h-3.1z"/>
<path d="M263.1 118.2h3.1v.4h-3.1z"/>
<path d="M263.1 117.4h3.1v.4h-3.1z"/>
<path d="M263.1 172.6h3.1v.4h-3.1z"/>
<path d="M263.1 171.8h3.1v.4h-3.1z"/>
<path d="M105.7 38.5h3.1v.4h-3.1z"/>
<path d="M105.7 37.7h3.1v.4h-3.1z"/>
<path d="M127.1 29.4h3.1v.4h-3.1z"/>
<path d="M127.1 28.6h3.1v.4h-3.1z"/>
<path d="M134.9 29.4h3.1v.4h-3.1z"/>
<path d="M134.9 28.6h3.1v.4h-3.1z"/>
<path d="M142.7 29.4h3.1v.4h-3.1z"/>
<path d="M142.7 28.6h3.1v.4h-3.1z"/>
<path d="M127.1 54.1h3.1v.3h-3.1z"/>
<path d="M127.1 53.3h3.1v.4h-3.1z"/>
<path d="M289.3 97.6h1.2v3.9h-1.2z"/>
<path d="M49.4 134.9h.4v3.1h-.4z"/>
<path d="M50.1 134.9h.4v3.1h-.4z"/>
<path d="M56 146.6h.4v3h-.4z"/>
<path d="M55.2 146.6h.4v3h-.4z"/>
<path d="M56 154.3h.4v3.1h-.4z"/>
<path d="M55.2 154.3h.4v3.1h-.4z"/>
<path d="M74.7 36.6h3v.3h-3z"/>
<path d="M74.7 35.8h3v.4h-3z"/>
<path d="M27.8 32.9h.7h-.7z"/>
<path d="M28.1 32.6h.1v.6h-.1z"/>
<path d="M244.5 28.6h.4v1.9h-.4z"/>
<path d="M243.7 28.6h.4v1.9h-.4z"/>
<path d="M244.5 32.5h.4v1.9h-.4z"/>
<path d="M243.7 32.5h.4v1.9h-.4z"/>
<path d="M230.9 36.4h.4v1.9h-.4z"/>
<path d="M230.1 36.4h.4v1.9h-.4z"/>
<path d="M230.9 40.3h.4v1.9h-.4z"/>
<path d="M230.1 40.3h.4v1.9h-.4z"/>
<path d="M242.5 53.8h.4v2h-.4z"/>
<path d="M241.8 53.8h.3v2h-.3z"/>
<path d="M238.7 55.8h.3v1.9h-.3z"/>
<path d="M237.9 55.8h.4v1.9h-.4z"/>
<path d="M37.7 118.2h3.1v.4h-3.1z"/>
<path d="M37.7 117.4h3.1v.4h-3.1z"/>
<path d="M45.5 118.2h3.1v.4h-3.1z"/>
<path d="M45.5 117.4h3.1v.4h-3.1z"/>
<path d="M160.1 102.6h3.1v.4h-3.1z"/>
<path d="M160.1 101.9h3.1v.3h-3.1z"/>
<path d="M263.7 97.1h2v1h-2z"/>
<path d="M263.7 141.8h2v.9h-2z"/>
<path d="M270 156.8h1v2h-1z"/>
<path d="M263 87.2h.7v.1h-.7z"/>
<path d="M263.3 87h.1v.6h-.1z"/>
<path d="M263 132h.7h-.7z"/>
<path d="M263.3 131.7h.1v.6h-.1z"/>
<path d="M249.5 89h3.1v.4h-3.1z"/>
<path d="M249.5 88.2h3.1v.4h-3.1z"/>
<path d="M255.4 135.7h3.1v.3h-3.1z"/>
<path d="M255.4 134.9h3.1v.4h-3.1z"/>
</g>
<g fill="none" stroke="#800000" stroke-width=".21">
<path d="M27.6 33.4h3.9M35.4 27.6h11.6v7.8h-11.6zM54.1 33.4h1.4v3.9h-1.4zM63.6 28.6l1.9 1-1.9 .9zM63.6 22.8l1.9 .9-1.9 1zM64.5 33.4h5.9v5.9h-5.9v-.8h2v-4.3h-2zM66 28.8v-.2h-.5v1.9h-.5v-.2M66 23v-.2h-.5v1.9h-.5v-.2M66.9 35.4h.7M66.9 37.3h.7M67.2 35v.8M67.8 33.4v.6h1.2v-.6"/>
<path d="M67.8 39.3v-.6h1.2v.6M88.3 35.4h2.9M111.2 27.6h3.9M111.7 35.4h2.9M119.4 35.4h2.9M127.2 35.4h2.9M135 35.4h2.9M142.7 35.4h3M143.6 20.8l.6-.9 .6 .9M190.3 28.6l.5-1 .6 1M196.7 29.6h9.7v27.2h-9.7zM234.6 32.5l.9-1 1 1"/>
<path d="M251.1 27.6h11.6v31.1h-11.6zM28.1 43.2h2.9M47.5 43.2h2.9M53.4 43.2h2.9M59.2 43.2h2.9M74.7 43.2h2.9M87.3 46.1l.5-1 .6 1M105.8 43.2h2.9M111.2 52.9h3.9M128.1 46.1l.6-1 .5 1M189.4 58.7h2.9M197.1 50.9h.9v3.9h-.9"/>
<path d="M231.6 52.2h3.9v1.4h-3.9zM88.3 62.6h2.9M111.7 60.7h2.9M119.4 60.7h2.9M127.2 60.7h2.9M226.8 60.7h1.9M126.1 90.8l.6-1 .6 1M168.9 92.7l.6-1 .6 1M190.3 92.7l.5-1 .6 1M200 92.7l.6-1 .5 1M207.8 92.7l.5-1 .6 1M225.1 99.5h1.4v3.9h-1.4z"/>
<path d="M225.2 92.7l.6-1 .6 1M241.4 83.3h3.9v1.3h-3.9zM249.6 95.6h2.9M262.7 87.9h3.9M264.7 95.6v2M46.5 110.2l.5-1 .6 1M56.2 110.2l.5-1 .6 1M60.6 114.4h3.9v1.3h-3.9zM66.5 104.9v.4M66.5 101.5l.9 3.4M70.4 113.1h23.3v60.3h-23.3zM76.7 101.5h2.9"/>
<path d="M118 107.8l.9 3.4M118.9 107.3v.5M121.9 107.8l.9 3.4M122.8 107.3v.5M125.8 107.8l.9 3.4M126.7 107.3v.5M129.6 107.8l1 3.4M130.6 107.3v.5M133.5 107.8l1 3.4M134.5 107.3v.5M160.2 109.2h3M183.1 101.5h33v46.6h-33z"/>
<path d="M264 107.3h1.4v3.9h-1.4zM29.5 135v2.9M37.8 124.8h2.9M41.2 135v2.9M45.6 124.8h2.9M52.9 139.6h3.8v1.4h-3.8zM118.3 126.7h1.3v3.9h-1.3zM122.2 126.7h1.3v3.9h-1.3zM126 126.7h1.4v3.9h-1.4zM129.9 126.7h1.4v3.9h-1.4zM133.8 126.7h1.4v3.9h-1.4zM139.3 136.4h2l-1 2z"/>
<path d="M139.3 138.4h2M139.6 126.7h1.4v3.9h-1.4zM148.6 136.4h2.9M158.4 125.9h2.7M158.4 127.5h2.7M158.6 126.4h2.3v.6h-2.3zM163 124.8h1.3v3.9h-1.3zM249.1 129.9h3.9v1.4h-3.9zM262.7 132.5h3.9M263.2 124.8h2.9M29.5 143.2h5.9v2h-5.9zM35.4 142.3h-1l-4.1 3.9"/>
<path d="M45.1 141.6h3.9v1.3h-3.9zM49.5 157.8h2.9M61.2 151.2h2.7M61.2 152.8h2.7M61.4 151.7h2.4v.6h-2.4zM125.3 144.2h2.9M138.9 144.2h2.9M169.9 157.8h3M170.7 146.2h1.4v3.9h-1.4zM177.7 157.8h2.9M178.5 142.3h1.4v3.9h-1.4zM191.3 157.8h2.9"/>
<path d="M204.9 157.8h3M222.4 157.8h2.9M223.2 140.3h1.4v3.9h-1.4zM230.2 157.8h2.9M255.5 142.3h2.9M264.7 140.3v2M270.5 157.8h2M65 175.3h2.9M247.7 179.2h2.9M248.5 161.7h1.3v3.9h-1.3zM263.2 179.2h2.9M264 161.7h1.4v3.9h-1.4z"/>
<path d="M276.8 165.6h2.9"/>
</g>
<g fill="#800000" stroke="#800000" stroke-width=".16">
<path d="M113.1 28.3h.6l.9 .3 .5 .4-.1 .1a2.76 2.76 0 0 0-1.9-.6z" fill-rule="evenodd"/>
<path d="M111.2 29l.5-.4 .8-.2 .6-.1v.2a3.1 3.1 0 0 0-1.8 .6z" fill-rule="evenodd"/>
<path d="M113.1 53.6h.6l.9 .3 .5 .3-.1 .2a3.1 3.1 0 0 0-1.9-.7z" fill-rule="evenodd"/>
<path d="M111.2 54.2l.1-.1a2.84 2.84 0 0 1 1.8-.5v.2a2.79 2.79 0 0 0-1.8 .6z" fill-rule="evenodd"/>
<path d="M29.5 34.1l1.5 .3 .5 .4-.1 .1a3.1 3.1 0 0 0-1.9-.6z" fill-rule="evenodd"/>
<path d="M27.6 34.8l.5-.3 .8-.3 .6-.1v.2a2.9 2.9 0 0 0-1.8 .6z" fill-rule="evenodd"/>
<path d="M66.3 101.3h.4v.3h-.4z" fill-rule="evenodd"/>
<path d="M66.3 105.2l.2-.1 .2 .1v.3l-.2 .1-.2-.1z" fill-rule="evenodd"/>
<path d="M118.8 111h.3v.4h-.3l-.1-.2z" fill-rule="evenodd"/>
<path d="M118.8 107.1h.3v.4h-.2h-.1l-.1-.2z" fill-rule="evenodd"/>
<path d="M122.6 111h.4l.1 .2-.1 .2h-.4z" fill-rule="evenodd"/>
<path d="M122.6 107.1h.4l.1 .2-.1 .2h-.2h-.2z" fill-rule="evenodd"/>
<path d="M126.5 111h.4v.4h-.4z" fill-rule="evenodd"/>
<path d="M126.5 107.1h.4v.4h-.2h-.2z" fill-rule="evenodd"/>
<path d="M130.4 111h.4v.4h-.4l-.1-.2z" fill-rule="evenodd"/>
<path d="M130.4 107.1h.4v.4h-.2h-.2l-.1-.2z" fill-rule="evenodd"/>
<path d="M263.9 95.9a.98 .98 0 0 1 1.1-.3 .98 .98 0 0 1 .7 .9h-2z" fill-rule="evenodd"/>
<path d="M263.7 98.6h2a.97 .97 0 0 1-1 1 .97 .97 0 0 1-1-1z" fill-rule="evenodd"/>
<path d="M263.9 140.5a.98 .98 0 0 1 1.1-.2 .98 .98 0 0 1 .7 .9h-2z" fill-rule="evenodd"/>
<path d="M263.7 143.3h2a.97 .97 0 0 1-1 1 .97 .97 0 0 1-1-1z" fill-rule="evenodd"/>
<path d="M271.6 156.8a.97 .97 0 0 1 1 1 .97 .97 0 0 1-1 1z" fill-rule="evenodd"/>
<path d="M268.8 157.1l.7-.3v2a.97 .97 0 0 1-1-.6 .97 .97 0 0 1 .3-1.1z" fill-rule="evenodd"/>
<path d="M264.7 88.5l.6 .1 .8 .3 .6 .3-.2 .1a2.9 2.9 0 0 0-1.8-.6z" fill-rule="evenodd"/>
<path d="M262.7 89.2l.6-.3 .8-.3 .6-.1v.2a3.1 3.1 0 0 0-1.8 .6z" fill-rule="evenodd"/>
<path d="M264.7 133.2l.6 .1 .8 .2 .6 .4-.2 .1a3.1 3.1 0 0 0-1.8-.6z" fill-rule="evenodd"/>
<path d="M262.7 133.9l.6-.3 .8-.3 .6-.1v.2a2.79 2.79 0 0 0-1.8 .6z" fill-rule="evenodd"/>
<path d="M134.3 111h.4v.2v.2h-.4z" fill-rule="evenodd"/>
<path d="M134.3 107.1h.4v.2v.2h-.2h-.2z" fill-rule="evenodd"/>
</g>
<path d="M.4 5.3h296.4v199.1h-296.4z" fill="none" stroke="#800000" stroke-width=".23"/>
<path d="M12.1 134.5h7.7v11.7h-7.7z" fill="none" stroke="#800000" stroke-width=".4"/>
<g fill="none" stroke="#008000" stroke-width=".16">
<path d="M23.7 23.7h38.9M29.5 23.7v7.8M29.5 37.3v3.9M29.5 29.6h3.9M49 31.5h5.8M49 33.4v7.8M49 29.6h13.6M54.8 39.3v1.9M60.6 29.6v5.8h2M62.6 37.3h-2v3.9M66.5 23.7h25.2M66.5 29.6h9.7"/>
<path d="M76.2 23.7v9.7M76.2 39.3v1.9M87.8 23.7v3.9h3.9M91.7 31.5h-1.9v1.9M105.3 31.5h2v3.9M105.3 23.7h38.9M113.1 23.7v2M113.1 31.5v1.9M120.9 23.7v2.6M120.9 32.1v1.3M128.7 23.7v2.6M128.7 32.1v1.3"/>
<path d="M136.4 23.7v2.6M136.4 32.1v1.3M144.2 21.8v4.5M144.2 32.1v1.3M187 39.3h5.8M187 35.4h5.8M187 33.4h5.8M190.8 29.6v7.7h2M227.8 39.3h21.3M227.8 37.3v21.4M233.6 37.3h15.5M235.5 33.4v7.8"/>
<path d="M241.4 29.6h-2v1.9h9.7M241.4 33.4h-2v2h9.7M247.2 29.6h1.9M247.2 33.4h1.9M87.8 47.1v5.8h3.9M87.8 49h3.9M91.7 56.8h-1.9v3.9M105.3 49h23.4M113.1 49v1.9M113.1 56.8v1.9M120.9 49v1.9M120.9 56.8v1.9"/>
<path d="M128.7 47.1v3.8M128.7 56.8v1.9M187 43.2h5.8M190.8 54.8h2M190.8 52.9h2M190.8 50.9h2M190.8 49h2M192.8 41.2h-2v15.6M227.8 56.8h7.7M227.8 54.8h11.6M227.8 52.9h1.9M233.6 41.2h15.5"/>
<path d="M237.5 52.9h11.6M241.4 56.8h7.7M245.3 54.8h3.8M247.2 50.9h1.9M247.2 49h1.9M247.2 43.2h1.9M247.2 45.1h1.9M247.2 47.1h1.9M66.5 99.5h11.6M122.8 95.6v9.7M126.7 91.7v13.6M130.6 95.6v9.7"/>
<path d="M169.5 97.6h-7.8v1.9M169.5 93.7v29.1h9.7M188.9 97.6v-2h3.9v2M190.8 93.7v3.9M196.7 97.6v-2h5.8v2M198.6 95.6v2M200.6 93.7v3.9M206.4 97.6v-2h3.9v2M208.3 93.7v3.9M225.8 93.7v3.9M237.5 84h1.9M247.2 84h17.5v1.9"/>
<path d="M251.1 84v1.9M251.1 91.7v2M264.7 91.7v2M268.6 97.6h13.6M282.2 99.5h-13.6v42.8M47 113.1h-7.7v2M47 111.2v3.9M56.7 115.1h2M56.7 117h11.7M56.7 111.2v25.2M56.7 119h11.7M66.5 107.3v7.8h1.9"/>
<path d="M95.6 115.1h23.3M95.6 117h27.2M95.6 119h31.1M118.9 105.3v-9.7h15.6v9.7M118.9 113.1v11.7M122.8 113.1v11.7M126.7 113.1v11.7M130.6 113.1v11.7M134.5 113.1v11.7M161.7 105.3v2M220 113.1h3.9M220 115.1h3.9"/>
<path d="M220 117h3.9M225.8 105.3v3.9h-5.8M235.5 103.4h29.2M264.7 101.5v3.8M264.7 113.1v2M282.2 101.5h-11.7v52.4M21.8 136.4h5.8M39.3 120.9v1.9M43.2 136.4h3.8M47 120.9v1.9M52.9 136.4h15.5M56.7 120.9h11.7"/>
<path d="M56.7 122.8h11.7M62.6 132.5h5.8M95.6 120.9h35M95.6 132.5h5.9M95.6 136.4h5.9M95.6 138.4h5.9M95.6 124.8h44.7M95.6 122.8h38.9M95.6 134.5h5.9M118.9 132.5v5.9h15.6v-5.9M122.8 132.5v5.9M126.7 132.5v9.8"/>
<path d="M130.6 132.5v5.9M140.3 132.5v2M150 132.5h2M152 120.9h-2v13.6M157.8 120.9h9.7v3.9h11.7M159.7 120.9v3.9M159.7 128.7v3.8M163.6 120.9v1.9M163.6 130.6v1.9M179.2 126.7h-11.7v5.8h-9.7M179.2 130.6v9.7M220 132.5h3.9"/>
<path d="M220 124.8h11.6v11.6M220 130.6h3.9v7.8M220 136.4h3.9M220 134.5h3.9M243.3 130.6h3.9M255 130.6h9.7M256.9 130.6v1.9M256.9 138.4v1.9M264.7 120.9v1.9M264.7 136.4v2M21.8 140.3h29.1M21.8 144.2h5.8"/>
<path d="M21.8 142.3h21.4M37.3 144.2h5.9M50.9 142.3h17.5M52.9 148.1h-2v7.8h2M58.7 148.1h7.8v2h1.9M58.7 140.3h9.7M62.6 148.1v2M62.6 153.9v2M68.4 153.9h-1.9v2h-7.8M95.6 155.9h5.9M95.6 140.3h5.9M95.6 150.1h5.9"/>
<path d="M95.6 144.2h5.9M95.6 159.8h5.9M95.6 152h5.9M140.3 140.3v2M167.5 140.3h3.9v3.9M171.4 152v3.9M179.2 148.1v7.8M187 152v1.9h9.7v-1.9M188.9 152v1.9M190.8 152v1.9M192.8 152v3.9M194.7 152v1.9"/>
<path d="M204.4 152v1.9h5.9v-1.9M206.4 152v3.9M208.3 152v1.9M223.9 146.2v9.7M231.6 142.3v13.6M249.1 153.9v5.9M262.7 157.8h3.9M264.7 146.2v7.7h-21.4M264.7 157.8v2M274.4 157.8h3.9v5.8M66.5 165.6h1.9M66.5 167.5h1.9"/>
<path d="M66.5 169.5h1.9M66.5 171.4h1.9M68.4 163.6h-1.9v9.8M95.6 163.6h5.9M95.6 165.6h5.9M95.6 161.7h5.9M249.1 167.5v2M249.1 175.3v1.9M264.7 167.5v2M264.7 175.3v1.9"/>
</g>
<g fill="#008000" stroke="#008000" stroke-width=".16">
<circle cx="194.7" cy="153.9" r=".38"/>
<circle cx="192.8" cy="153.9" r=".38"/>
<circle cx="190.8" cy="153.9" r=".38"/>
<circle cx="188.9" cy="153.9" r=".38"/>
<circle cx="206.4" cy="153.9" r=".38"/>
<circle cx="208.3" cy="153.9" r=".38"/>
<circle cx="150" cy="132.5" r=".38"/>
<circle cx="190.8" cy="54.8" r=".38"/>
<circle cx="190.8" cy="52.9" r=".38"/>
<circle cx="190.8" cy="50.9" r=".38"/>
<circle cx="190.8" cy="49" r=".38"/>
<circle cx="50.9" cy="155.9" r=".38"/>
<circle cx="227.8" cy="52.9" r=".38"/>
<circle cx="227.8" cy="56.8" r=".38"/>
<circle cx="227.8" cy="54.8" r=".38"/>
<circle cx="227.8" cy="41.2" r=".38"/>
<circle cx="227.8" cy="39.3" r=".38"/>
<circle cx="126.7" cy="138.4" r=".38"/>
<circle cx="122.8" cy="138.4" r=".38"/>
<circle cx="130.6" cy="138.4" r=".38"/>
<circle cx="66.5" cy="165.6" r=".38"/>
<circle cx="66.5" cy="167.5" r=".38"/>
<circle cx="66.5" cy="169.5" r=".38"/>
<circle cx="66.5" cy="171.4" r=".38"/>
<circle cx="163.6" cy="120.9" r=".38"/>
<circle cx="159.7" cy="120.9" r=".38"/>
<circle cx="163.6" cy="132.5" r=".38"/>
<circle cx="159.7" cy="132.5" r=".38"/>
<circle cx="264.7" cy="103.4" r=".38"/>
<circle cx="249.1" cy="153.9" r=".38"/>
<circle cx="264.7" cy="157.8" r=".38"/>
<circle cx="113.1" cy="23.7" r=".38"/>
<circle cx="120.9" cy="23.7" r=".38"/>
<circle cx="136.4" cy="23.7" r=".38"/>
<circle cx="128.7" cy="23.7" r=".38"/>
<circle cx="144.2" cy="23.7" r=".38"/>
<circle cx="208.3" cy="95.6" r=".38"/>
<circle cx="190.8" cy="95.6" r=".38"/>
<circle cx="169.5" cy="97.6" r=".38"/>
<circle cx="87.8" cy="49" r=".38"/>
<circle cx="235.5" cy="37.3" r=".38"/>
<circle cx="235.5" cy="41.2" r=".38"/>
<circle cx="47" cy="113.1" r=".38"/>
<circle cx="122.8" cy="95.6" r=".38"/>
<circle cx="126.7" cy="95.6" r=".38"/>
<circle cx="130.6" cy="95.6" r=".38"/>
<circle cx="56.7" cy="115.1" r=".38"/>
<circle cx="56.7" cy="117" r=".38"/>
<circle cx="56.7" cy="119" r=".38"/>
<circle cx="56.7" cy="120.9" r=".38"/>
<circle cx="56.7" cy="122.8" r=".38"/>
<circle cx="56.7" cy="136.4" r=".38"/>
<circle cx="113.1" cy="49" r=".38"/>
<circle cx="120.9" cy="49" r=".38"/>
<circle cx="128.7" cy="49" r=".38"/>
<circle cx="200.6" cy="95.6" r=".38"/>
<circle cx="198.6" cy="95.6" r=".38"/>
<circle cx="179.2" cy="132.5" r=".38"/>
<circle cx="179.2" cy="134.5" r=".38"/>
<circle cx="179.2" cy="136.4" r=".38"/>
<circle cx="223.9" cy="136.4" r=".38"/>
<circle cx="223.9" cy="132.5" r=".38"/>
<circle cx="223.9" cy="134.5" r=".38"/>
<circle cx="179.2" cy="111.2" r=".38"/>
<circle cx="179.2" cy="113.1" r=".38"/>
<circle cx="179.2" cy="109.2" r=".38"/>
<circle cx="179.2" cy="115.1" r=".38"/>
<circle cx="179.2" cy="117" r=".38"/>
<circle cx="179.2" cy="120.9" r=".38"/>
<circle cx="179.2" cy="119" r=".38"/>
<circle cx="62.6" cy="148.1" r=".38"/>
<circle cx="62.6" cy="155.9" r=".38"/>
<circle cx="60.6" cy="29.6" r=".38"/>
<circle cx="76.2" cy="23.7" r=".38"/>
<circle cx="87.8" cy="23.7" r=".38"/>
<circle cx="76.2" cy="29.6" r=".38"/>
<circle cx="118.9" cy="115.1" r=".38"/>
<circle cx="122.8" cy="117" r=".38"/>
<circle cx="126.7" cy="119" r=".38"/>
<circle cx="130.6" cy="120.9" r=".38"/>
<circle cx="29.5" cy="29.6" r=".38"/>
<circle cx="29.5" cy="23.7" r=".38"/>
<circle cx="134.5" cy="122.8" r=".38"/>
<circle cx="256.9" cy="130.6" r=".38"/>
<circle cx="251.1" cy="84" r=".38"/>
<circle cx="66.5" cy="115.1" r=".38"/>
</g>
<use href="#words"/>
</svg>
